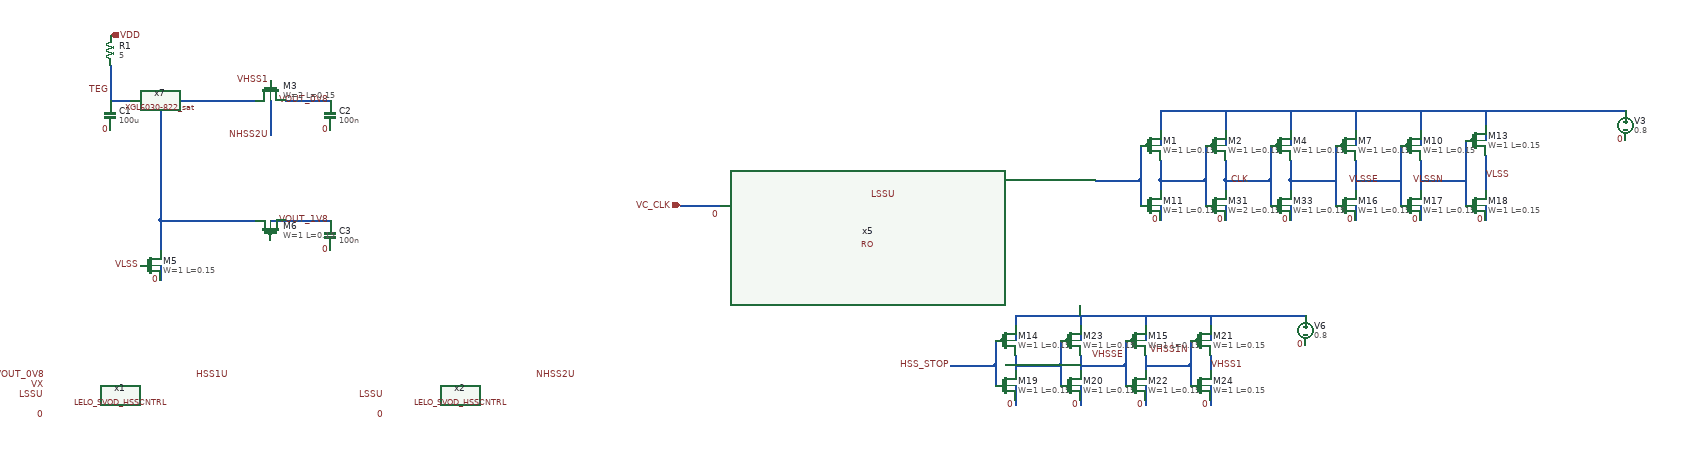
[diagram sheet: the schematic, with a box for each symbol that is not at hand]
v {xschem version=3.4.8RC file_version=1.2}
G {}
K {}
V {}
S {}
E {}
N -510 -330 -510 -260 {lab=TEG}
N -280 -260 -220 -260 {lab=VX}
N -410 -260 -280 -260 {lab=VX}
N -410 -260 -410 -100 {lab=VX}
N -490 -260 -470 -260 {lab=TEG}
N 1590 -50 1590 -20 {lab=0}
N 1460 -100 1550 -100 {lab=#net1}
N 1980 -140 1980 -80 {lab=VLSSE}
N 1980 -50 1980 -20 {lab=0}
N 1940 -170 1940 -50 {lab=#net2}
N 1590 -100 1680 -100 {lab=#net3}
N -510 -260 -490 -260 {lab=TEG}
N 2110 -140 2110 -80 {lab=VLSSN}
N 2110 -50 2110 -20 {lab=0}
N 2070 -170 2070 -50 {lab=VLSSE}
N 1980 -100 2070 -100 {lab=VLSSE}
N 2240 -150 2240 -80 {lab=VLSS}
N 2240 -50 2240 -20 {lab=0}
N 2200 -180 2200 -50 {lab=VLSSN}
N 2110 -100 2200 -100 {lab=VLSSN}
N -160 -260 -70 -260 {lab=VOUT_0V8}
N 1590 -240 2170 -240 {lab=#net4}
N 1980 -240 1980 -200 {lab=#net4}
N 2110 -240 2110 -200 {lab=#net4}
N 2240 -240 2240 -210 {lab=#net4}
N 1590 -240 1590 -200 {lab=#net4}
N 1590 -140 1590 -100 {lab=#net3}
N 1590 -100 1590 -80 {lab=#net3}
N 1550 -170 1550 -100 {lab=#net1}
N 1550 -100 1550 -50 {lab=#net1}
N 1300 170 1300 190 {lab=#net5}
N 1430 170 1430 190 {lab=#net5}
N 1300 310 1300 340 {lab=0}
N 1430 310 1430 340 {lab=0}
N 1170 270 1260 270 {lab=HSS_STOP}
N 1260 220 1260 270 {lab=HSS_STOP}
N 1260 270 1260 310 {lab=HSS_STOP}
N 1300 250 1300 280 {lab=#net6}
N 1300 340 1300 350 {lab=0}
N 1300 270 1390 270 {lab=#net6}
N 1390 220 1390 270 {lab=#net6}
N 1390 270 1390 310 {lab=#net6}
N 1430 250 1430 280 {lab=VHSSE}
N 1430 340 1430 350 {lab=0}
N 1560 170 1560 190 {lab=#net5}
N 1560 310 1560 340 {lab=0}
N 1430 270 1520 270 {lab=VHSSE}
N 1520 220 1520 270 {lab=VHSSE}
N 1520 270 1520 310 {lab=VHSSE}
N 1560 250 1560 280 {lab=VHSS1N}
N 1560 340 1560 350 {lab=0}
N 1690 170 1690 190 {lab=#net5}
N 1690 310 1690 340 {lab=0}
N 1650 220 1650 270 {lab=VHSS1N}
N 1650 270 1650 310 {lab=VHSS1N}
N 1690 250 1690 280 {lab=VHSS1}
N 1690 340 1690 350 {lab=0}
N 1590 -200 1590 -170 {lab=#net4}
N 1980 -200 1980 -170 {lab=#net4}
N 2110 -200 2110 -170 {lab=#net4}
N 2240 -210 2240 -180 {lab=#net4}
N 1300 190 1300 220 {lab=#net5}
N 1430 190 1430 220 {lab=#net5}
N 1560 190 1560 220 {lab=#net5}
N 1690 190 1690 220 {lab=#net5}
N 1300 170 1880 170 {lab=#net5}
N 1720 -50 1720 -20 {lab=0}
N 1720 -100 1810 -100 {lab=CLK}
N 1720 -240 1720 -200 {lab=#net4}
N 1720 -140 1720 -100 {lab=CLK}
N 1720 -100 1720 -80 {lab=CLK}
N 1680 -170 1680 -100 {lab=#net3}
N 1680 -100 1680 -50 {lab=#net3}
N 1720 -200 1720 -170 {lab=#net4}
N 1850 -50 1850 -20 {lab=0}
N 1850 -100 1940 -100 {lab=#net2}
N 1850 -240 1850 -200 {lab=#net4}
N 1850 -140 1850 -100 {lab=#net2}
N 1850 -100 1850 -80 {lab=#net2}
N 1810 -170 1810 -100 {lab=CLK}
N 1810 -100 1810 -50 {lab=CLK}
N 1850 -200 1850 -170 {lab=#net4}
N 2170 -240 2520 -240 {lab=#net4}
N 1560 270 1650 270 {lab=VHSS1N}
N 630 -50 710 -50 {lab=VC_CLK}
N -280 -20 -220 -20 {lab=VX}
N -410 -20 -280 -20 {lab=VX}
N -160 -20 -70 -20 {lab=VOUT_1V8}
N -410 -100 -410 -20 {lab=VX}
N -410 -20 -410 40 {lab=VX}
N -410 70 -410 100 {lab=0}
N -190 -20 -160 -20 {lab=VOUT_1V8}
N -190 -260 -190 -190 {lab=NHSS2U}
C {devices/ipin.sym} -510 -390 0 1 {name=p2 lab=VDD}
C {devices/lab_pin.sym} -410 -260 3 1 {name=p3 sig_type=std_logic lab=VX}
C {devices/res.sym} -510 -360 0 1 {name=R1
value=5
footprint=1206
device=resistor
m=1}
C {devices/lab_pin.sym} 1300 350 3 0 {name=p77 sig_type=std_logic lab=0}
C {LELO_SVOD_SKY130A/RO.sym} 860 -50 0 0 {name=x5}
C {devices/lab_pin.sym} 710 -30 3 0 {name=p13 sig_type=std_logic lab=0}
C {devices/lab_pin.sym} 1770 -100 1 1 {name=p14 sig_type=std_logic lab=CLK}
C {devices/lab_pin.sym} 1590 -20 3 0 {name=p15 sig_type=std_logic lab=0}
C {devices/lab_pin.sym} 1980 -20 3 0 {name=p17 sig_type=std_logic lab=0}
C {devices/lab_pin.sym} 2240 -110 0 1 {name=p30 sig_type=std_logic lab=VLSS}
C {devices/lab_pin.sym} -450 70 0 0 {name=p66 sig_type=std_logic lab=VLSS}
C {devices/lab_pin.sym} 1430 350 3 0 {name=p4 sig_type=std_logic lab=0}
C {devices/capa.sym} -510 -230 0 1 {name=C1
m=1
value=100u
footprint=1206
device="ceramic capacitor"}
C {devices/lab_pin.sym} -510 -200 3 0 {name=p7 sig_type=std_logic lab=0}
C {sky130_fd_pr/nfet_01v8_lvt.sym} -430 70 0 0 {name=M5
W=1
L=0.15
nf=2
mult=6800
ad="expr('int((@nf + 1)/2) * @W / @nf * 0.29')"
pd="expr('2*int((@nf + 1)/2) * (@W / @nf + 0.29)')"
as="expr('int((@nf + 2)/2) * @W / @nf * 0.29')"
ps="expr('2*int((@nf + 2)/2) * (@W / @nf + 0.29)')"
nrd="expr('0.29 / @W ')" nrs="expr('0.29 / @W ')"
sa=0 sb=0 sd=0
model=nfet_01v8_lvt
spiceprefix=X
}
C {devices/lab_pin.sym} 2110 -20 3 0 {name=p51 sig_type=std_logic lab=0}
C {devices/lab_pin.sym} 2240 -20 3 0 {name=p90 sig_type=std_logic lab=0}
C {devices/lab_pin.sym} -510 -280 2 1 {name=p93 sig_type=std_logic lab=TEG}
C {devices/capa.sym} -70 -230 0 1 {name=C2
m=1
value=100n
footprint=1206
device="ceramic capacitor"}
C {devices/lab_pin.sym} -70 -200 3 0 {name=p1 sig_type=std_logic lab=0}
C {devices/lab_pin.sym} -70 -260 1 0 {name=p35 sig_type=std_logic lab=VOUT_0V8}
C {devices/lab_pin.sym} 2160 -100 3 1 {name=p70 sig_type=std_logic lab=VLSSN}
C {sky130_fd_pr/nfet_01v8.sym} 1570 -50 0 0 {name=M11
W=1
L=0.15
nf=1 
mult=1
ad="expr('int((@nf + 1)/2) * @W / @nf * 0.29')"
pd="expr('2*int((@nf + 1)/2) * (@W / @nf + 0.29)')"
as="expr('int((@nf + 2)/2) * @W / @nf * 0.29')"
ps="expr('2*int((@nf + 2)/2) * (@W / @nf + 0.29)')"
nrd="expr('0.29 / @W ')" nrs="expr('0.29 / @W ')"
sa=0 sb=0 sd=0
model=nfet_01v8
spiceprefix=X
}
C {sky130_fd_pr/nfet_01v8.sym} 1960 -50 0 0 {name=M16
W=1
L=0.15
nf=1 
mult=27
ad="expr('int((@nf + 1)/2) * @W / @nf * 0.29')"
pd="expr('2*int((@nf + 1)/2) * (@W / @nf + 0.29)')"
as="expr('int((@nf + 2)/2) * @W / @nf * 0.29')"
ps="expr('2*int((@nf + 2)/2) * (@W / @nf + 0.29)')"
nrd="expr('0.29 / @W ')" nrs="expr('0.29 / @W ')"
sa=0 sb=0 sd=0
model=nfet_01v8
spiceprefix=X
}
C {sky130_fd_pr/nfet_01v8.sym} 2090 -50 0 0 {name=M17
W=1
L=0.15
nf=1 
mult=81
ad="expr('int((@nf + 1)/2) * @W / @nf * 0.29')"
pd="expr('2*int((@nf + 1)/2) * (@W / @nf + 0.29)')"
as="expr('int((@nf + 2)/2) * @W / @nf * 0.29')"
ps="expr('2*int((@nf + 2)/2) * (@W / @nf + 0.29)')"
nrd="expr('0.29 / @W ')" nrs="expr('0.29 / @W ')"
sa=0 sb=0 sd=0
model=nfet_01v8
spiceprefix=X
}
C {sky130_fd_pr/nfet_01v8.sym} 2220 -50 0 0 {name=M18
W=1
L=0.15
nf=1 
mult=243
ad="expr('int((@nf + 1)/2) * @W / @nf * 0.29')"
pd="expr('2*int((@nf + 1)/2) * (@W / @nf + 0.29)')"
as="expr('int((@nf + 2)/2) * @W / @nf * 0.29')"
ps="expr('2*int((@nf + 2)/2) * (@W / @nf + 0.29)')"
nrd="expr('0.29 / @W ')" nrs="expr('0.29 / @W ')"
sa=0 sb=0 sd=0
model=nfet_01v8
spiceprefix=X
}
C {sky130_fd_pr/nfet_01v8.sym} 1280 310 0 0 {name=M19
W=1
L=0.15
nf=1 
mult=1
ad="expr('int((@nf + 1)/2) * @W / @nf * 0.29')"
pd="expr('2*int((@nf + 1)/2) * (@W / @nf + 0.29)')"
as="expr('int((@nf + 2)/2) * @W / @nf * 0.29')"
ps="expr('2*int((@nf + 2)/2) * (@W / @nf + 0.29)')"
nrd="expr('0.29 / @W ')" nrs="expr('0.29 / @W ')"
sa=0 sb=0 sd=0
model=nfet_01v8
spiceprefix=X
}
C {sky130_fd_pr/nfet_01v8.sym} 1410 310 0 0 {name=M20
W=1
L=0.15
nf=1 
mult=3
ad="expr('int((@nf + 1)/2) * @W / @nf * 0.29')"
pd="expr('2*int((@nf + 1)/2) * (@W / @nf + 0.29)')"
as="expr('int((@nf + 2)/2) * @W / @nf * 0.29')"
ps="expr('2*int((@nf + 2)/2) * (@W / @nf + 0.29)')"
nrd="expr('0.29 / @W ')" nrs="expr('0.29 / @W ')"
sa=0 sb=0 sd=0
model=nfet_01v8
spiceprefix=X
}
C {devices/lab_pin.sym} 1690 270 0 1 {name=p18 sig_type=std_logic lab=VHSS1}
C {devices/lab_pin.sym} 1560 350 3 0 {name=p21 sig_type=std_logic lab=0}
C {sky130_fd_pr/nfet_01v8.sym} 1540 310 0 0 {name=M22
W=1
L=0.15
nf=1 
mult=9
ad="expr('int((@nf + 1)/2) * @W / @nf * 0.29')"
pd="expr('2*int((@nf + 1)/2) * (@W / @nf + 0.29)')"
as="expr('int((@nf + 2)/2) * @W / @nf * 0.29')"
ps="expr('2*int((@nf + 2)/2) * (@W / @nf + 0.29)')"
nrd="expr('0.29 / @W ')" nrs="expr('0.29 / @W ')"
sa=0 sb=0 sd=0
model=nfet_01v8
spiceprefix=X
}
C {devices/lab_pin.sym} 1690 350 3 0 {name=p55 sig_type=std_logic lab=0}
C {sky130_fd_pr/nfet_01v8.sym} 1670 310 0 0 {name=M24
W=1
L=0.15
nf=1 
mult=27
ad="expr('int((@nf + 1)/2) * @W / @nf * 0.29')"
pd="expr('2*int((@nf + 1)/2) * (@W / @nf + 0.29)')"
as="expr('int((@nf + 2)/2) * @W / @nf * 0.29')"
ps="expr('2*int((@nf + 2)/2) * (@W / @nf + 0.29)')"
nrd="expr('0.29 / @W ')" nrs="expr('0.29 / @W ')"
sa=0 sb=0 sd=0
model=nfet_01v8
spiceprefix=X
}
C {devices/lab_pin.sym} 1650 240 2 1 {name=p97 sig_type=std_logic lab=VHSS1N}
C {devices/vsource.sym} 2520 -210 0 0 {name=V3 value=0.8 savecurrent=false}
C {devices/lab_pin.sym} 2520 -180 1 1 {name=p5 sig_type=std_logic lab=0}
C {devices/vsource.sym} 1880 200 0 0 {name=V6 value=0.8 savecurrent=false}
C {devices/lab_pin.sym} 1880 230 1 1 {name=p16 sig_type=std_logic lab=0}
C {devices/lab_pin.sym} 1720 -20 3 0 {name=p88 sig_type=std_logic lab=0}
C {sky130_fd_pr/nfet_01v8.sym} 1700 -50 0 0 {name=M31
W=2
L=0.15
nf=1 
mult=3
ad="expr('int((@nf + 1)/2) * @W / @nf * 0.29')"
pd="expr('2*int((@nf + 1)/2) * (@W / @nf + 0.29)')"
as="expr('int((@nf + 2)/2) * @W / @nf * 0.29')"
ps="expr('2*int((@nf + 2)/2) * (@W / @nf + 0.29)')"
nrd="expr('0.29 / @W ')" nrs="expr('0.29 / @W ')"
sa=0 sb=0 sd=0
model=nfet_01v8
spiceprefix=X
}
C {devices/lab_pin.sym} 1850 -20 3 0 {name=p89 sig_type=std_logic lab=0}
C {sky130_fd_pr/nfet_01v8.sym} 1830 -50 0 0 {name=M33
W=1
L=0.15
nf=1 
mult=9
ad="expr('int((@nf + 1)/2) * @W / @nf * 0.29')"
pd="expr('2*int((@nf + 1)/2) * (@W / @nf + 0.29)')"
as="expr('int((@nf + 2)/2) * @W / @nf * 0.29')"
ps="expr('2*int((@nf + 2)/2) * (@W / @nf + 0.29)')"
nrd="expr('0.29 / @W ')" nrs="expr('0.29 / @W ')"
sa=0 sb=0 sd=0
model=nfet_01v8
spiceprefix=X
}
C {LELO_SVOD_SKY130A/XGL6030-822_sat.sym} -440 -260 3 1 {name=x7}
C {devices/lab_pin.sym} -190 -300 1 0 {name=p101 sig_type=std_logic lab=VHSS1}
C {devices/lab_pin.sym} 1170 270 0 0 {name=p9 sig_type=std_logic lab=HSS_STOP}
C {devices/lab_pin.sym} 1520 250 2 1 {name=p11 sig_type=std_logic lab=VHSSE}
C {devices/ipin.sym} 630 -50 0 0 {name=p45 lab=VC_CLK}
C {sky130_fd_pr/pfet_01v8.sym} 1570 -170 0 0 {name=M1
W=1
L=0.15
nf=1
mult=1
ad="expr('int((@nf + 1)/2) * @W / @nf * 0.29')"
pd="expr('2*int((@nf + 1)/2) * (@W / @nf + 0.29)')"
as="expr('int((@nf + 2)/2) * @W / @nf * 0.29')"
ps="expr('2*int((@nf + 2)/2) * (@W / @nf + 0.29)')"
nrd="expr('0.29 / @W ')" nrs="expr('0.29 / @W ')"
sa=0 sb=0 sd=0
model=pfet_01v8
spiceprefix=X
}
C {sky130_fd_pr/pfet_01v8.sym} 1700 -170 0 0 {name=M2
W=1
L=0.15
nf=1
mult=3
ad="expr('int((@nf + 1)/2) * @W / @nf * 0.29')"
pd="expr('2*int((@nf + 1)/2) * (@W / @nf + 0.29)')"
as="expr('int((@nf + 2)/2) * @W / @nf * 0.29')"
ps="expr('2*int((@nf + 2)/2) * (@W / @nf + 0.29)')"
nrd="expr('0.29 / @W ')" nrs="expr('0.29 / @W ')"
sa=0 sb=0 sd=0
model=pfet_01v8
spiceprefix=X
}
C {sky130_fd_pr/pfet_01v8.sym} 1830 -170 0 0 {name=M4
W=1
L=0.15
nf=1
mult=9
ad="expr('int((@nf + 1)/2) * @W / @nf * 0.29')"
pd="expr('2*int((@nf + 1)/2) * (@W / @nf + 0.29)')"
as="expr('int((@nf + 2)/2) * @W / @nf * 0.29')"
ps="expr('2*int((@nf + 2)/2) * (@W / @nf + 0.29)')"
nrd="expr('0.29 / @W ')" nrs="expr('0.29 / @W ')"
sa=0 sb=0 sd=0
model=pfet_01v8
spiceprefix=X
}
C {sky130_fd_pr/pfet_01v8.sym} 1960 -170 0 0 {name=M7
W=1
L=0.15
nf=1
mult=27
ad="expr('int((@nf + 1)/2) * @W / @nf * 0.29')"
pd="expr('2*int((@nf + 1)/2) * (@W / @nf + 0.29)')"
as="expr('int((@nf + 2)/2) * @W / @nf * 0.29')"
ps="expr('2*int((@nf + 2)/2) * (@W / @nf + 0.29)')"
nrd="expr('0.29 / @W ')" nrs="expr('0.29 / @W ')"
sa=0 sb=0 sd=0
model=pfet_01v8
spiceprefix=X
}
C {sky130_fd_pr/pfet_01v8.sym} 2090 -170 0 0 {name=M10
W=1
L=0.15
nf=1
mult=81
ad="expr('int((@nf + 1)/2) * @W / @nf * 0.29')"
pd="expr('2*int((@nf + 1)/2) * (@W / @nf + 0.29)')"
as="expr('int((@nf + 2)/2) * @W / @nf * 0.29')"
ps="expr('2*int((@nf + 2)/2) * (@W / @nf + 0.29)')"
nrd="expr('0.29 / @W ')" nrs="expr('0.29 / @W ')"
sa=0 sb=0 sd=0
model=pfet_01v8
spiceprefix=X
}
C {sky130_fd_pr/pfet_01v8.sym} 2220 -180 0 0 {name=M13
W=1
L=0.15
nf=1
mult=243
ad="expr('int((@nf + 1)/2) * @W / @nf * 0.29')"
pd="expr('2*int((@nf + 1)/2) * (@W / @nf + 0.29)')"
as="expr('int((@nf + 2)/2) * @W / @nf * 0.29')"
ps="expr('2*int((@nf + 2)/2) * (@W / @nf + 0.29)')"
nrd="expr('0.29 / @W ')" nrs="expr('0.29 / @W ')"
sa=0 sb=0 sd=0
model=pfet_01v8
spiceprefix=X
}
C {sky130_fd_pr/pfet_01v8.sym} 1280 220 0 0 {name=M14
W=1
L=0.15
nf=1
mult=1
ad="expr('int((@nf + 1)/2) * @W / @nf * 0.29')"
pd="expr('2*int((@nf + 1)/2) * (@W / @nf + 0.29)')"
as="expr('int((@nf + 2)/2) * @W / @nf * 0.29')"
ps="expr('2*int((@nf + 2)/2) * (@W / @nf + 0.29)')"
nrd="expr('0.29 / @W ')" nrs="expr('0.29 / @W ')"
sa=0 sb=0 sd=0
model=pfet_01v8
spiceprefix=X
}
C {sky130_fd_pr/pfet_01v8.sym} 1540 220 0 0 {name=M15
W=1
L=0.15
nf=1
mult=9
ad="expr('int((@nf + 1)/2) * @W / @nf * 0.29')"
pd="expr('2*int((@nf + 1)/2) * (@W / @nf + 0.29)')"
as="expr('int((@nf + 2)/2) * @W / @nf * 0.29')"
ps="expr('2*int((@nf + 2)/2) * (@W / @nf + 0.29)')"
nrd="expr('0.29 / @W ')" nrs="expr('0.29 / @W ')"
sa=0 sb=0 sd=0
model=pfet_01v8
spiceprefix=X
}
C {sky130_fd_pr/pfet_01v8.sym} 1670 220 0 0 {name=M21
W=1
L=0.15
nf=1
mult=27
ad="expr('int((@nf + 1)/2) * @W / @nf * 0.29')"
pd="expr('2*int((@nf + 1)/2) * (@W / @nf + 0.29)')"
as="expr('int((@nf + 2)/2) * @W / @nf * 0.29')"
ps="expr('2*int((@nf + 2)/2) * (@W / @nf + 0.29)')"
nrd="expr('0.29 / @W ')" nrs="expr('0.29 / @W ')"
sa=0 sb=0 sd=0
model=pfet_01v8
spiceprefix=X
}
C {sky130_fd_pr/pfet_01v8.sym} 1410 220 0 0 {name=M23
W=1
L=0.15
nf=1
mult=3
ad="expr('int((@nf + 1)/2) * @W / @nf * 0.29')"
pd="expr('2*int((@nf + 1)/2) * (@W / @nf + 0.29)')"
as="expr('int((@nf + 2)/2) * @W / @nf * 0.29')"
ps="expr('2*int((@nf + 2)/2) * (@W / @nf + 0.29)')"
nrd="expr('0.29 / @W ')" nrs="expr('0.29 / @W ')"
sa=0 sb=0 sd=0
model=pfet_01v8
spiceprefix=X
}
C {devices/lab_pin.sym} 2030 -100 3 1 {name=p50 sig_type=std_logic lab=VLSSE}
C {sky130_fd_pr/nfet_01v8_lvt.sym} -190 -280 1 0 {name=M3
W=2
L=0.15
nf=2
mult=1
ad="expr('int((@nf + 1)/2) * @W / @nf * 0.29')"
pd="expr('2*int((@nf + 1)/2) * (@W / @nf + 0.29)')"
as="expr('int((@nf + 2)/2) * @W / @nf * 0.29')"
ps="expr('2*int((@nf + 2)/2) * (@W / @nf + 0.29)')"
nrd="expr('0.29 / @W ')" nrs="expr('0.29 / @W ')"
sa=0 sb=0 sd=0
model=nfet_01v8_lvt
spiceprefix=X
}
C {devices/capa.sym} -70 10 0 1 {name=C3
m=1
value=100n
footprint=1206
device="ceramic capacitor"}
C {devices/lab_pin.sym} -70 40 3 0 {name=p6 sig_type=std_logic lab=0}
C {devices/lab_pin.sym} -70 -20 1 0 {name=p8 sig_type=std_logic lab=VOUT_1V8}
C {sky130_fd_pr/pfet_01v8.sym} -190 0 1 1 {name=M6
W=1
L=0.15
nf=1
mult=1
ad="expr('int((@nf + 1)/2) * @W / @nf * 0.29')"
pd="expr('2*int((@nf + 1)/2) * (@W / @nf + 0.29)')"
as="expr('int((@nf + 2)/2) * @W / @nf * 0.29')"
ps="expr('2*int((@nf + 2)/2) * (@W / @nf + 0.29)')"
nrd="expr('0.29 / @W ')" nrs="expr('0.29 / @W ')"
sa=0 sb=0 sd=0
model=pfet_01v8
spiceprefix=X
}
C {devices/lab_pin.sym} 1010 -70 0 1 {name=p10 sig_type=std_logic lab=LSSU}
C {devices/lab_pin.sym} -410 100 3 0 {name=p12 sig_type=std_logic lab=0}
C {LELO_SVOD_SKY130A/LELO_SVOD_HSSCNTRL.sym} -490 330 0 0 {name=x1}
C {LELO_SVOD_SKY130A/LELO_SVOD_HSSCNTRL.sym} 190 330 0 0 {name=x2}
C {devices/lab_pin.sym} -640 370 3 0 {name=p19 sig_type=std_logic lab=0}
C {devices/lab_pin.sym} 40 370 3 0 {name=p20 sig_type=std_logic lab=0}
C {devices/lab_pin.sym} -340 290 2 0 {name=p22 sig_type=std_logic lab=HSS1U}
C {devices/lab_pin.sym} 340 290 2 0 {name=p23 sig_type=std_logic lab=NHSS2U}
C {devices/lab_pin.sym} 40 330 0 0 {name=p24 sig_type=std_logic lab=LSSU}
C {devices/lab_pin.sym} -640 330 0 0 {name=p25 sig_type=std_logic lab=LSSU}
C {devices/lab_pin.sym} -640 310 2 1 {name=p26 sig_type=std_logic lab=VX}
C {devices/lab_pin.sym} -640 290 0 0 {name=p27 sig_type=std_logic lab=VOUT_0V8}
C {devices/lab_pin.sym} -190 -190 3 0 {name=p28 sig_type=std_logic lab=NHSS2U}
